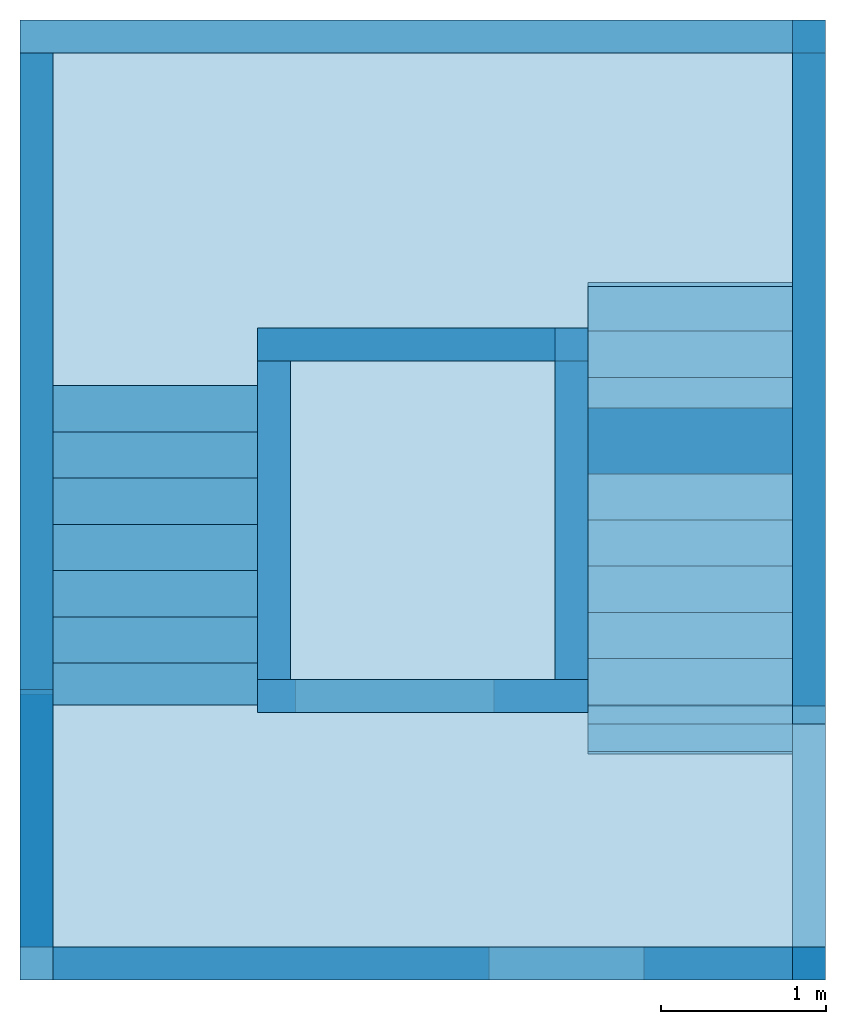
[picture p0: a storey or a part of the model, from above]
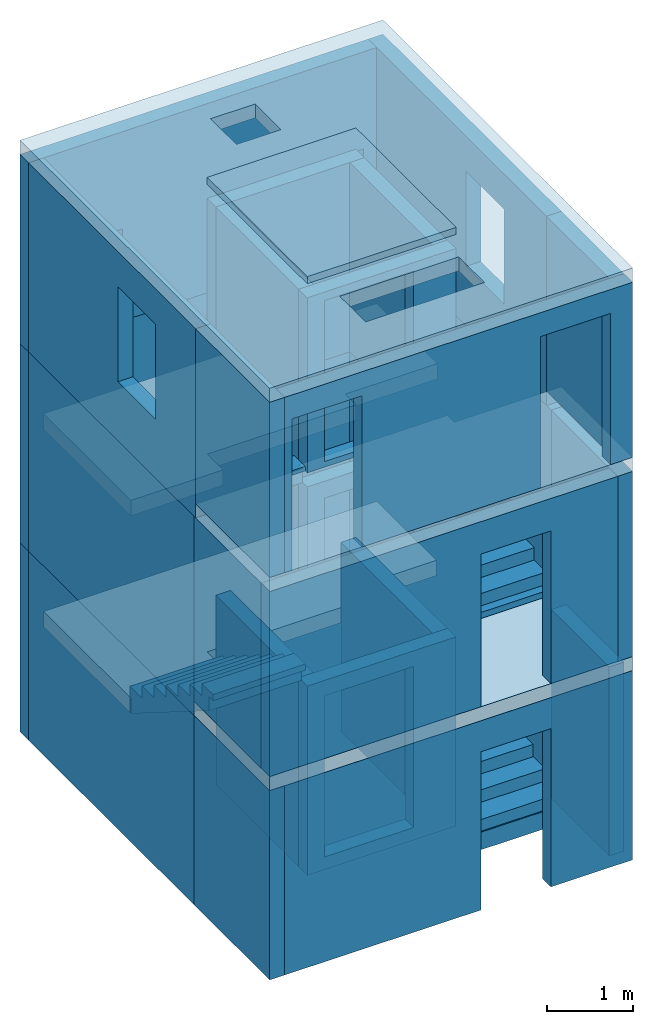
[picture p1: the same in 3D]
Properties of the parts of a building model (IFC4)

# File
Description: no view
File name: IHB 121.2 Treppenhaus.ifc
Time: 2022-11-06T08:55:36
Author: Recktenwald Kevin
Organization: CDS Bauingenieure AG, Berneckerstrasse 231 + 233 ï CH-9435 Heerbrugg
Written by: EDMsix Version 2.0.209.92 Dec 12 2020
Made in: Allplan 2022.1 29.09.2022 - 12:14:56

# IfcProject, Privat Kevin
AllplanAttributes - Bauherr: Andrea und Urs Thür; Architekt: Kuster Bauplaung GmbH; Normalhöhennull: 467.80 m.ü.M.; Bauvorhaben: MFH Thür; Bauunternehmer Straße: Säntisstrasse 8; Bauunternehmer Plz/Ort: 9450 Lüchingen; Bauherr Straße: Fähnerenstrasse 12; Bauherr Plz/Ort: 9450 Altstätten; Architekt Straße: Birkenweg 4; Architekt Plz/Ort: 9444 Diepoldsau; Bauvorhaben Straße: Rebhaldenstrasse 1a; Bauvorhaben Plz/Ort: 9450 Altstätten; Projektnummer: 00.00; Bauunternehmer: Finger AG

# IfcSite, Überbauung
RefLatitude: 48, 0, 0, 0; RefLongitude: 0, 0, 0, 0; RefElevation: 467.8 m

# IfcBuildingStorey, Fundation & Aushub
In: Gebäude A
Elevation: 0 m

# IfcOpeningElement: Opening (16)
In: Fundation & Aushub
AllplanAttributes - Object Layer Attributes #1, Gewerk: Betonarbeiten; Object Layer Attributes #1, Einheit: m³
Qto_OpeningElementBaseQuantities - Depth: 0.2 m
Name | Object Layer Attributes #1, Türanschlag | Object Layer Attributes #1, Allright_Bauteil_ID | Object Layer Attributes #1, Objektname | Area (m2) | Volume (m3) | Height (m) | Width (m)
Türöffnung | DIN L | 1003Tür0000000077 | Türöffnung | 2.115 | 0.423 | 2.25 | 0.94
Türöffnung | DIN L | 1003Tür0000000081 | Türöffnung | 1.689 | 0.338 | 1.33 | 1.27
Türöffnung | DIN L | 1003Tür0000000073 | Türöffnung | 1.144 | 0.229 | 1.3 | 0.88
Türöffnung | DIN L | 1003Tür0000000009 | Türöffnung | 2.748 | 0.55 | 2.29 | 1.2
Türöffnung | DIN L | 1003Tür0000000032 | Türöffnung | 1.656 | 0.331 | 1.38 | 1.2
Türöffnung | DIN L | 1005Tür0000000200 | Türöffnung | 2.748 | 0.55 | 2.29 | 1.2
Türöffnung | DIN L | 1005Tür0000000257 | Türöffnung | 1.17 | 0.234 | 1.33 | 0.88
Türöffnung | DIN L | 1005Tür0000000254 | Türöffnung | 1.17 | 0.234 | 1.33 | 0.88
Türöffnung | DIN L | 1005Tür0000000231 | Türöffnung | 2.04 | 0.408 | 2.17 | 0.94
Fensteröffnung |  | 1007Fen0000000024 | Fensteröffnung | 1.153 | 0.231 | 1.31 | 0.88
Fensteröffnung |  | 1007Fen0000000031 | Fensteröffnung | 1.153 | 0.231 | 1.31 | 0.88
Türöffnung | DIN L | 1007Tür0000000065 | Türöffnung | 7.238 | 1.448 | 7.7 | 0.94
Türöffnung | DIN L | 1007Tür0000000063 | Türöffnung | 7.238 | 1.448 | 7.7 | 0.94
Türöffnung | DIN L | 1007Tür0000000017 | Türöffnung | 2.748 | 0.55 | 2.29 | 1.2
Fensteröffnung |  | 1007Fen0000000049 | Fensteröffnung | 1.188 | 0.238 | 1.35 | 0.88
Fensteröffnung |  | 1007Fen0000000052 | Fensteröffnung | 1.188 | 0.238 | 1.35 | 0.88

# IfcSlab (6)
In: Fundation & Aushub
PredefinedType: FLOOR; Material: Beton
AllplanAttributes - Gewerk: Betonarbeiten; Material: Beton; Einheit: m³; Objektname: Decke
Pset_SlabCommon - Status: Neubau; LoadBearing: yes
Name | 2D interaktion | Allright_Bauteil_ID | GrossArea (m2) | Depth (m) | NetArea (m2) | GrossVolume (m3) | Perimeter (m) | NetVolume (m3) | Length (m) | Width (m)
 | yes | 1004De 0000000160 | 8.404 | 1.722 | 8.404 | 1.681 | 13.4 | 1.681 | 4.88 | 0.2
 |  | 1004De 0000000153 | 7.56 | 1.391 | 7.56 | 1.663 | 13 | 1.663 | 5.434 | 0.22
 |  | 1006De 0000000134 | 7.608 | 1.24 | 7.608 | 1.674 | 13.03 | 1.674 | 6.136 | 0.22
 | yes | 1006De 0000000147 | 8.517 | 4.88 | 8.516 | 1.703 | 13.4 | 1.703 | 1.745 | 0.2
 | yes | 1008De 0000000142 | 23.969 | 5.815 | 23.969 | 4.794 | 35.25 | 4.794 | 4.122 | 0.2
 | yes | 1008De 0000000008 | 4.66 | 2 | 4.66 | 0.932 | 8.66 | 0.775 | 2.33 | 0.2

# IfcWall (34)
In: Fundation & Aushub
AllplanAttributes - Einheit: m³; Objektname: Gesamtwand; Object Layer Attributes #1, Status: Neubau; Object Layer Attributes #1, Gewerk: Betonarbeiten; Object Layer Attributes #1, Material: Beton; Object Layer Attributes #1, Einheit: m³; Object Layer Attributes #1, Objektname: Wand
Name | Material | Allright_Bauteil_ID | Object Layer Attributes #1, Tragendes Bauteil | Object Layer Attributes #1, Allright_Bauteil_ID | LoadBearing | Width (m) | GrossSideArea (m2) | NetSideArea (m2) | GrossVolume (m3) | Length (m) | NetVolume (m3) | GrossFootprintArea (m2) | Height (m)
 | Beton 0.2 m | 1003HWa0000000044 | yes | 1003Wa 0000000097 | yes | 0.2 | 4.73 | 4.73 | 0.946 | 1.758 | 0.946 | 0.352 | 2.69 | AllplanAttributes - Object Layer Attributes #1, 2D interaktion: yes
 | Beton 0.2 m | 1003HWa0000000046 | yes | 1003Wa 0000000101 | yes | 0.2 | 10.374 | 10.374 | 2.075 | 3.857 | 2.075 | 0.771 | 2.69 | AllplanAttributes - Object Layer Attributes #1, 2D interaktion: yes
 | Beton 0.2 m | 1003HWa0000000002 | yes | 1003Wa 0000000085 | yes | 0.2 | 12.589 | 10.474 | 2.518 | 4.68 | 2.095 | 0.936 | 2.69 | AllplanAttributes - Object Layer Attributes #1, 2D interaktion: yes
 | Beton 0.2 m | 1003HWa0000000051 | yes | 1003Wa 0000000099 | yes | 0.2 | 10.935 | 10.935 | 2.187 | 4.065 | 2.187 | 0.813 | 2.69 | AllplanAttributes - Object Layer Attributes #1, 2D interaktion: yes
 | Beton 0.2 m | 1003HWa0000000048 | yes | 1003Wa 0000000094 | yes | 0.2 | 3.631 | 3.632 | 0.726 | 1.35 | 0.726 | 0.27 | 2.69 | AllplanAttributes - Object Layer Attributes #1, 2D interaktion: yes
 | Beton 0.2 m | 1003HWa0000000013 | yes | 1003Wa 0000000091 | yes | 0.2 | 13.127 | 10.294 | 2.625 | 4.88 | 2.059 | 0.976 | 2.69 | AllplanAttributes - Object Layer Attributes #1, 2D interaktion: yes
 | Beton 0.2 m | 1003HWa0000000021 | yes | 1003Wa 0000000105 | yes | 0.2 | 5.192 | 5.192 | 1.038 | 1.93 | 1.038 | 0.386 | 2.69 | AllplanAttributes - Object Layer Attributes #1, 2D interaktion: yes
 | Beton 0.2 m | 1003HWa0000000018 | yes | 1003Wa 0000000103 | yes | 0.2 | 5.73 | 5.73 | 1.146 | 2.13 | 1.146 | 0.426 | 2.69 | AllplanAttributes - Object Layer Attributes #1, 2D interaktion: yes
 | Beton 0.2 m | 1003HWa0000000004 | yes | 1003Wa 0000000111 | yes | 0.2 | 5.38 | 2.632 | 1.076 | 2 | 0.526 | 0.4 | 2.69 | AllplanAttributes - Object Layer Attributes #1, 2D interaktion: yes
 | Beton 0.2 m | 1003HWa0000000025 | yes | 1003Wa 0000000108 | yes | 0.2 | 4.842 | 3.186 | 0.968 | 1.8 | 0.637 | 0.36 | 2.69 | AllplanAttributes - Object Layer Attributes #1, 2D interaktion: yes
 | Beton 0.2 m | 1005HWa0000000171 | yes | 1005Wa 0000000203 | yes | 0.2 | 5.66 | 2.912 | 1.132 | 2 | 0.582 | 0.4 | 2.83
 | Beton 0.2 m | 1005HWa0000000177 |  | 1005Wa 0000000261 | yes | 0.2 | 13.81 | 11.469 | 2.762 | 4.88 | 2.294 | 0.976 | 2.83
 | Beton 0.2 m | 1005HWa0000000179 | yes | 1005Wa 0000000207 | yes | 0.2 | 5.66 | 5.66 | 1.132 | 2 | 1.132 | 0.4 | 2.83
 | Beton 0.2 m | 1005HWa0000000181 | yes | 1005Wa 0000000209 | yes | 0.2 | 5.462 | 5.462 | 1.092 | 1.93 | 1.092 | 0.386 | 2.83
 | Beton 0.2 m | 1005HWa0000000183 | yes | 1005Wa 0000000205 | yes | 0.2 | 5.462 | 5.462 | 1.092 | 1.93 | 1.092 | 0.386 | 2.83
 | Beton 0.2 m | 1005HWa0000000169 | no | 1005Wa 0000000234 | yes | 0.2 | 12.308 | 10.268 | 2.462 | 4.68 | 2.054 | 0.936 | 2.63 | AllplanAttributes - Object Layer Attributes #1, 2D interaktion: yes
 | Beton 0.2 m | 1005HWa0000000191 |  | 1005Wa 0000000213 | yes | 0.2 | 10.914 | 10.914 | 2.183 | 3.857 | 2.183 | 0.771 | 2.83
 | Beton 0.2 m | 1005HWa0000000189 | no | 1005Wa 0000000224 | yes | 0.2 | 4.098 | 4.098 | 0.82 | 1.558 | 0.82 | 0.312 | 2.63 | AllplanAttributes - Object Layer Attributes #1, 2D interaktion: yes
 | Beton 0.2 m | 1005HWa0000000187 |  | 1005Wa 0000000211 | yes | 0.2 | 11.504 | 11.504 | 2.301 | 4.065 | 2.301 | 0.813 | 2.83
 | Beton 0.2 m | 1005HWa0000000185 | no | 1005Wa 0000000244 | yes | 0.2 | 4.077 | 4.077 | 0.815 | 1.55 | 0.815 | 0.31 | 2.63 | AllplanAttributes - Object Layer Attributes #1, 2D interaktion: yes
 | Beton 0.2 m | 1007HWa0000000002 |  | 1007Wa 0000000073 | yes | 0.2 | 12.589 | 10.283 | 2.518 | 4.68 | 2.057 | 0.936 | 2.69
 | Beton 0.2 m | 1007HWa0000000007 |  | 1007Wa 0000000088 | yes | 0.2 | 5.38 | 5.38 | 1.076 | 2 | 1.076 | 0.4 | 2.69
 | Beton 0.2 m | 1007HWa0000000184 | no | 1007Wa 0000000190 | yes | 0.2 | 4.299 | 4.299 | 0.86 | 1.727 | 0.86 | 0.345 | 2.49 | AllplanAttributes - Object Layer Attributes #1, 2D interaktion: yes
 | Beton 0.2 m | 1007HWa0000000004 | no | 1007Wa 0000000069 | yes | 0.2 | 11.653 | 7.611 | 2.331 | 4.68 | 1.522 | 0.936 | 2.49 | AllplanAttributes - Object Layer Attributes #1, 2D interaktion: yes
 | Beton 0.2 m | 1007HWa0000000212 | no | 1007Wa 0000000220 | yes | 0.2 | 3.635 | 3.635 | 0.727 | 1.46 | 0.727 | 0.292 | 2.49 | AllplanAttributes - Object Layer Attributes #1, 2D interaktion: yes
 | Beton 0.2 m | 1007HWa0000000009 | no | 1007Wa 0000000086 | yes | 0.2 | 4.98 | 2.232 | 0.996 | 2 | 0.446 | 0.4 | 2.49 | AllplanAttributes - Object Layer Attributes #1, 2D interaktion: yes
 | Beton 0.2 m | 1007HWa0000000011 |  | 1007Wa 0000000092 | yes | 0.2 | 5.192 | 5.192 | 1.038 | 1.93 | 1.038 | 0.386 | 2.69
 | Beton 0.2 m | 1007HWa0000000013 |  | 1007Wa 0000000090 | yes | 0.2 | 5.192 | 5.192 | 1.038 | 1.93 | 1.038 | 0.386 | 2.69
 | Beton 0.2 m | 1007HWa0000000039 |  | 1007Wa 0000000083 | yes | 0.2 | 10.46 | 9.272 | 2.092 | 3.888 | 1.854 | 0.778 | 2.69
 | Beton 0.2 m | 1007HWa0000000041 |  | 1007Wa 0000000080 | yes | 0.2 | 11.177 | 9.989 | 2.235 | 4.155 | 1.998 | 0.831 | 2.69
 | Beton | 1009HWa0000000002 | yes | 1009Wa 0000000006 |  | 1.935 | 1.776 | 1.776 | 0.698 | 1.24 | 0.698 | 2.399 | 1.432 | AllplanAttributes - Object Layer Attributes #1, Material Architektur: Aussenwand Stahlbeton
 | Beton | 1009HWa0000000009 | yes | 1009Wa 0000000014 |  | 2.856 | 2.499 | 2.499 | 1.065 | 1.24 | 1.065 | 3.541 | 2.015 | AllplanAttributes - Object Layer Attributes #1, Material Architektur: Aussenwand Stahlbeton
 | Beton | 1009HWa0000000016 | yes | 1009Wa 0000000020 |  | 1.935 | 1.776 | 1.776 | 0.704 | 1.24 | 0.704 | 2.399 | 1.432 | AllplanAttributes - Object Layer Attributes #1, Material Architektur: Aussenwand Stahlbeton
 | Beton | 1009HWa0000000023 | yes | 1009Wa 0000000027 |  | 2.649 | 2.337 | 2.337 | 0.979 | 1.24 | 0.979 | 3.285 | 1.885 | AllplanAttributes - Object Layer Attributes #1, Material Architektur: Aussenwand Stahlbeton
